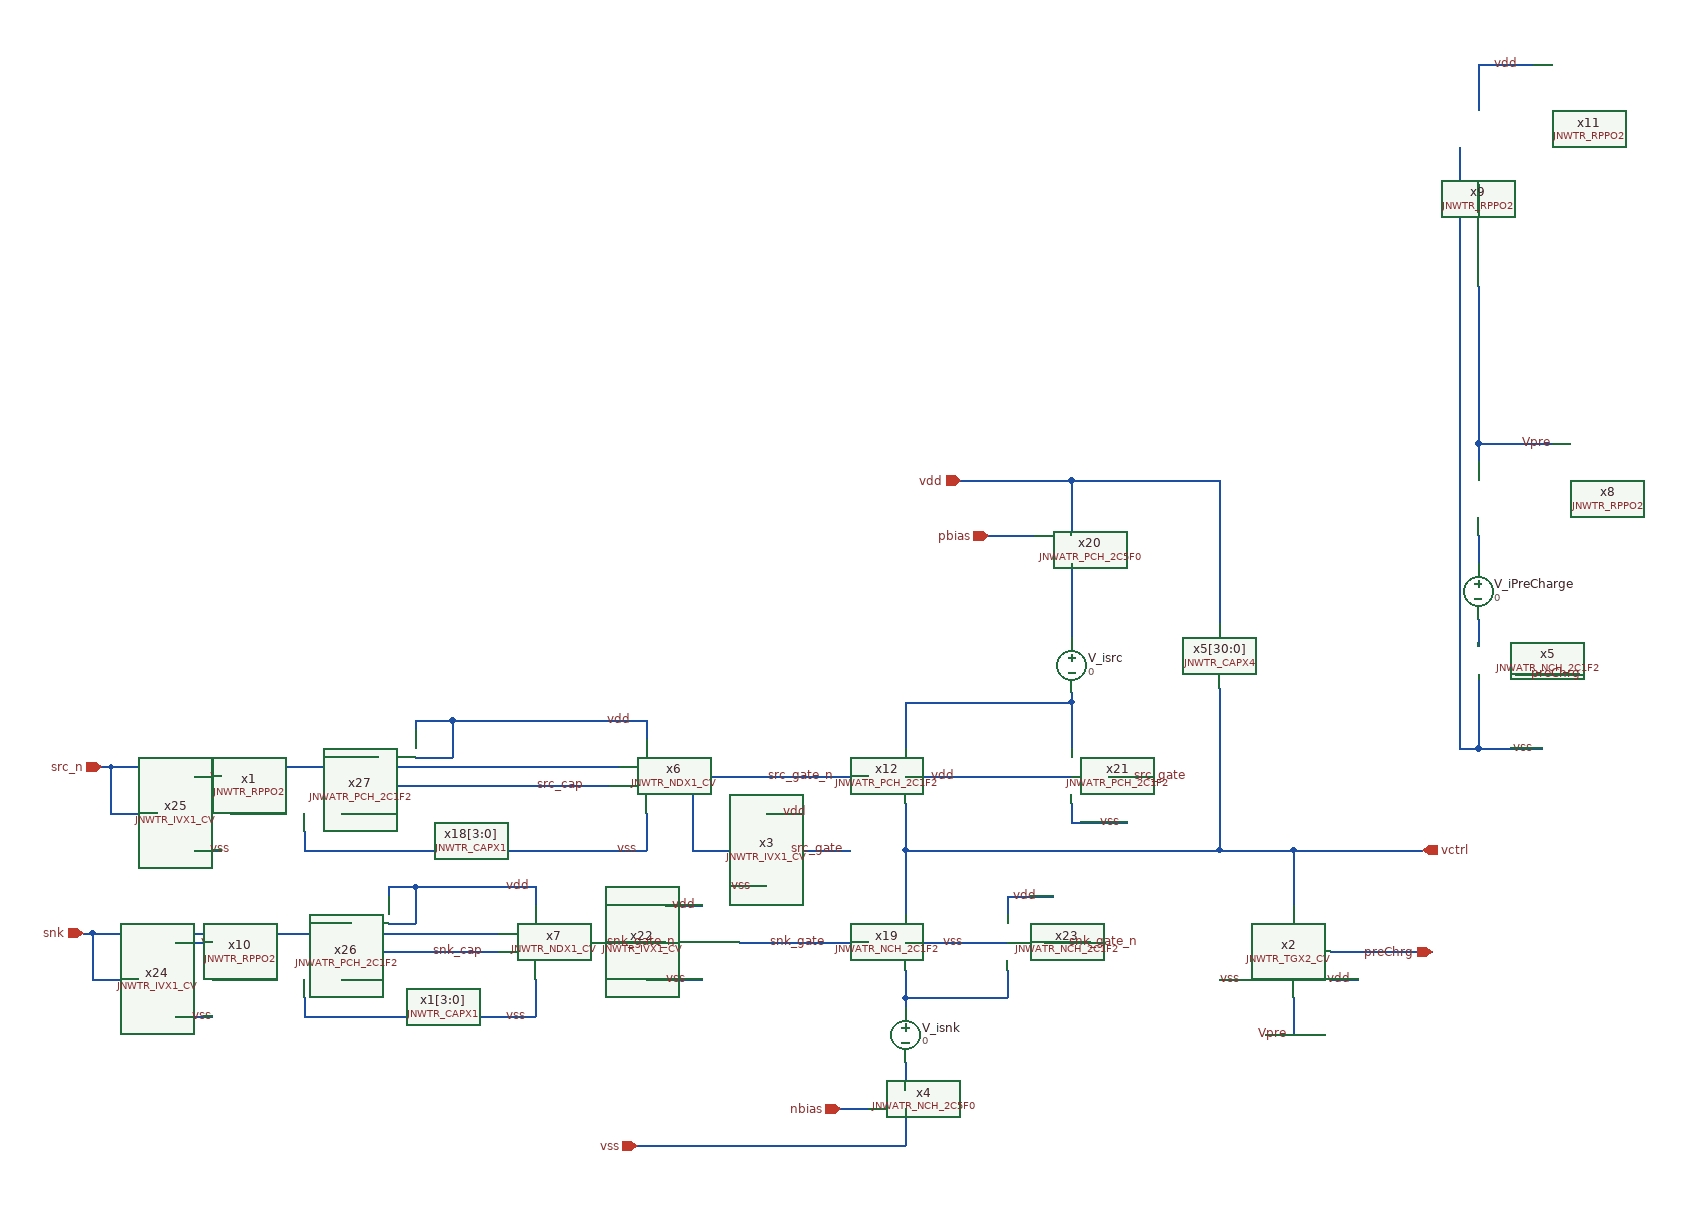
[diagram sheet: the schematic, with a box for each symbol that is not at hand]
v {xschem version=3.4.5 file_version=1.2
}
G {}
K {}
V {}
S {}
E {}
N 320 -700 440 -700 {
lab=vdd}
N 440 -700 440 -640 {
lab=vdd}
N 260 -20 260 20 {
lab=vss}
N 350 -640 400 -640 {
lab=pbias}
N 190 -20 220 -20 {
lab=nbias}
N 600 -475 600 -300 {
lab=vctrl}
N 600 -700 600 -545 {
lab=vdd}
N 720 -190 830 -190 {
lab=preChrg}
N 720 -160 750 -160 {
lab=vdd}
N 600 -160 630 -160 {
lab=vss}
N 680 -300 680 -240 {
lab=vctrl}
N 680 -300 820 -300 {
lab=vctrl}
N 600 -300 680 -300 {
lab=vctrl}
N 880 -740 960 -740 {
lab=Vpre}
N 680 -140 680 -100 {
lab=Vpre}
N 650 -100 680 -100 {
lab=Vpre}
N 260 -380 440 -380 {
lab=vdd}
N 260 -460 260 -410 {
lab=#net1}
N 260 -460 440 -460 {
lab=#net1}
N 260 -350 260 -300 {
lab=vctrl}
N 260 -300 600 -300 {
lab=vctrl}
N 440 -460 440 -410 {
lab=#net1}
N 440 -350 440 -330 {
lab=vss}
N 440 -330 500 -330 {
lab=vss}
N 480 -380 505 -380 {
lab=src_gate}
N -30 20 260 20 {
lab=vss}
N 370 -170 370 -140 {
lab=#net2}
N 260 -140 370 -140 {
lab=#net2}
N 260 -170 260 -140 {
lab=#net2}
N 370 -250 370 -230 {
lab=vdd}
N 370 -250 420 -250 {
lab=vdd}
N 410 -200 460 -200 {
lab=snk_gate_n}
N 440 -470 440 -460 {
lab=#net1}
N 260 -140 260 -130 {
lab=#net2}
N 260 -70 260 -40 {
lab=#net3}
N 260 -300 260 -230 {
lab=vctrl}
N 260 -200 370 -200 {
lab=vss}
N 440 -610 440 -530 {
lab=#net4}
N 440 -700 600 -700 {
lab=vdd}
N -380 -210 -180 -210 {
lab=snk}
N -20 -440 -20 -420 {
lab=vdd}
N -600 -390 -600 -340 {
lab=src_n}
N -610 -390 -600 -390 {
lab=src_n}
N -140 -260 -140 -240 {
lab=vdd}
N -140 -160 -140 -120 {
lab=vss}
N -620 -210 -620 -160 {
lab=snk}
N -330 -190 -330 -160 {
lab=snk_cap}
N -330 -190 -180 -190 {
lab=snk_cap}
N -320 -370 -320 -340 {
lab=src_cap}
N -390 -320 -390 -300 {
lab=vss}
N -20 -340 -20 -300 {
lab=vss}
N -320 -370 -60 -370 {
lab=src_cap}
N -350 -340 -320 -340 {
lab=src_cap}
N -390 -140 -390 -120 {
lab=vss}
N -350 -160 -330 -160 {
lab=snk_cap}
N 30 -380 220 -380 {
lab=src_gate_n}
N 95 -260 110 -260 {
lab=vss}
N 110 -340 125 -340 {
lab=vdd}
N 30 -380 30 -300 {
lab=src_gate_n}
N 30 -300 70 -300 {
lab=src_gate_n}
N 150 -300 200 -300 {
lab=src_gate}
N 80 -200 220 -200 {
lab=snk_gate}
N 0 -240 40 -240 {
lab=vdd}
N -510 -380 -480 -380 {
lab=vdd}
N -600 -340 -550 -340 {
lab=src_n}
N -470 -340 -430 -340 {
lab=#net5}
N -490 -160 -430 -160 {
lab=#net6}
N -620 -160 -570 -160 {
lab=snk}
N -530 -120 -490 -120 {
lab=vss}
N -530 -200 -490 -200 {
lab=vdd}
N -510 -300 -480 -300 {
lab=vss}
N -390 -300 -20 -300 {
lab=vss}
N -390 -120 -140 -120 {
lab=vss}
N -330 -390 -50 -390 {
lab=src_n}
N -20 -160 40 -160 {
lab=vss}
N -630 -210 -620 -210 {
lab=snk}
N -90 -200 0 -200 {
lab=snk_gate_n}
N -300 -260 -300 -250 {
lab=vdd}
N -270 -260 -140 -260 {
lab=vdd}
N -380 -220 -340 -220 {
lab=snk}
N -380 -220 -380 -210 {
lab=snk}
N -620 -210 -380 -210 {
lab=snk}
N -300 -220 -270 -220 {
lab=vdd}
N -270 -260 -270 -220 {
lab=vdd}
N -300 -260 -270 -260 {
lab=vdd}
N -330 -400 -310 -400 {
lab=src_n}
N -330 -400 -330 -390 {
lab=src_n}
N -600 -390 -330 -390 {
lab=src_n}
N -270 -440 -270 -430 {
lab=vdd}
N -230 -440 -20 -440 {
lab=vdd}
N -270 -400 -230 -400 {
lab=vdd}
N -230 -440 -230 -400 {
lab=vdd}
N -270 -440 -230 -440 {
lab=vdd}
N 880 -490 880 -410 {
lab=vss}
N 920 -490 990 -490 {
lab=preChrg}
N 880 -550 880 -520 {
lab=#net7}
N 880 -640 880 -610 {
lab=#net8}
N 880 -410 950 -410 {
lab=vss}
N 860 -410 880 -410 {
lab=vss}
N 880 -740 880 -720 {
lab=Vpre}
N 880 -1020 880 -990 {
lab=#net9}
N 880 -1150 880 -1100 {
lab=vdd}
N 880 -1150 940 -1150 {
lab=vdd}
N 880 -910 880 -740 {
lab=Vpre}
N 860 -1060 860 -410 {
lab=vss}
C {devices/ipin.sym} 320 -700 0 0 {name=p1 lab=vdd}
C {devices/opin.sym} 820 -300 0 0 {name=p2 lab=vctrl}
C {devices/ipin.sym} -30 20 0 0 {name=p3 lab=vss
}
C {devices/ipin.sym} 190 -20 0 0 {name=p6 lab=nbias
}
C {devices/ipin.sym} 350 -640 0 0 {name=p7 lab=pbias
}
C {JNW_TR_SKY130A/JNWTR_CAPX4.sym} 600 -485 0 0 {name=x5[30:0]}
C {devices/ipin.sym} 830 -190 2 0 {name=p10 lab=preChrg
}
C {devices/lab_wire.sym} 745 -160 0 0 {name=p8 sig_type=std_logic lab=vdd}
C {devices/lab_wire.sym} 895 -1150 0 1 {name=p19 sig_type=std_logic lab=vdd}
C {JNW_ATR_SKY130A/JNWATR_NCH_2C5F0.sym} 220 -20 0 0 {name=x4 }
C {devices/lab_wire.sym} 285 -380 0 1 {name=p22 sig_type=std_logic lab=vdd}
C {JNW_TR_SKY130A/JNWTR_TGX2_CV.sym} 680 -250 1 0 {name=x2 }
C {devices/lab_wire.sym} 915 -410 0 1 {name=p17 sig_type=std_logic lab=vss}
C {devices/lab_wire.sym} 625 -160 0 0 {name=p25 sig_type=std_logic lab=vss}
C {devices/lab_wire.sym} 925 -740 0 1 {name=p13 sig_type=std_logic lab=Vpre}
C {devices/lab_wire.sym} 675 -100 0 0 {name=p20 sig_type=std_logic lab=Vpre}
C {JNW_ATR_SKY130A/JNWATR_PCH_2C1F2.sym} 220 -380 0 0 {name=x12 }
C {JNW_ATR_SKY130A/JNWATR_NCH_2C1F2.sym} 220 -200 0 0 {name=x19 }
C {JNW_ATR_SKY130A/JNWATR_PCH_2C1F2.sym} 480 -380 0 1 {name=x21 }
C {devices/lab_wire.sym} 495 -330 0 0 {name=p26 sig_type=std_logic lab=vss}
C {devices/lab_wire.sym} 505 -380 0 1 {name=p28 sig_type=std_logic lab=src_gate}
C {JNW_ATR_SKY130A/JNWATR_NCH_2C1F2.sym} 410 -200 0 1 {name=x23 }
C {devices/lab_wire.sym} 325 -200 0 0 {name=p31 sig_type=std_logic lab=vss}
C {devices/lab_wire.sym} 405 -250 0 0 {name=p32 sig_type=std_logic lab=vdd}
C {devices/lab_wire.sym} 435 -200 0 1 {name=p33 sig_type=std_logic lab=snk_gate_n}
C {devices/vsource.sym} 440 -500 0 0 {name=V_isrc value=0 savecurrent=true}
C {devices/vsource.sym} 260 -100 0 0 {name=V_isnk value=0 savecurrent=true}
C {JNW_ATR_SKY130A/JNWATR_PCH_2C5F0.sym} 400 -640 0 0 {name=x20 }
C {devices/ipin.sym} -630 -210 0 0 {name=p9 lab=snk
}
C {devices/ipin.sym} -610 -390 0 0 {name=p11 lab=src_n}
C {devices/lab_wire.sym} -175 -260 0 1 {name=p14 sig_type=std_logic lab=vdd}
C {devices/lab_wire.sym} -175 -120 0 1 {name=p15 sig_type=std_logic lab=vss}
C {devices/lab_wire.sym} 185 -380 0 0 {name=p4 sig_type=std_logic lab=src_gate_n}
C {devices/lab_wire.sym} 175 -200 0 0 {name=p5 sig_type=std_logic lab=snk_gate}
C {devices/lab_wire.sym} -55 -300 0 1 {name=p12 sig_type=std_logic lab=vss}
C {devices/lab_wire.sym} -65 -440 0 1 {name=p16 sig_type=std_logic lab=vdd}
C {devices/lab_wire.sym} -85 -370 0 0 {name=p18 sig_type=std_logic lab=src_cap}
C {JNW_TR_SKY130A/JNWTR_CAPX1.sym} -210 -310 0 0 {name=x18[3:0]}
C {JNW_TR_SKY130A/JNWTR_CAPX1.sym} -240 -130 0 0 {name=x1[3:0]}
C {devices/lab_wire.sym} -195 -190 0 0 {name=p24 sig_type=std_logic lab=snk_cap}
C {JNW_TR_SKY130A/JNWTR_IVX1_CV.sym} 70 -300 0 0 {name=x3 }
C {devices/lab_wire.sym} 125 -340 0 1 {name=p21 sig_type=std_logic lab=vdd}
C {devices/lab_wire.sym} 95 -260 0 0 {name=p23 sig_type=std_logic lab=vss}
C {devices/lab_wire.sym} 195 -300 0 0 {name=p27 sig_type=std_logic lab=src_gate}
C {JNW_TR_SKY130A/JNWTR_IVX1_CV.sym} 0 -200 0 0 {name=x22 }
C {devices/lab_wire.sym} -65 -200 0 1 {name=p30 sig_type=std_logic lab=snk_gate_n}
C {JNW_TR_SKY130A/JNWTR_NDX1_CV.sym} -60 -370 0 0 {name=x6 }
C {JNW_TR_SKY130A/JNWTR_NDX1_CV.sym} -180 -190 0 0 {name=x7 }
C {devices/lab_wire.sym} 25 -160 0 0 {name=p34 sig_type=std_logic lab=vss}
C {devices/lab_wire.sym} 5 -240 0 1 {name=p35 sig_type=std_logic lab=vdd}
C {JNW_TR_SKY130A/JNWTR_IVX1_CV.sym} -570 -160 0 0 {name=x24 }
C {JNW_TR_SKY130A/JNWTR_IVX1_CV.sym} -550 -340 0 0 {name=x25 }
C {devices/lab_wire.sym} -515 -120 0 1 {name=p29 sig_type=std_logic lab=vss}
C {devices/lab_wire.sym} -495 -300 0 1 {name=p36 sig_type=std_logic lab=vss}
C {devices/lab_wire.sym} -505 -200 0 1 {name=p37 sig_type=std_logic lab=vdd}
C {devices/lab_wire.sym} -495 -380 0 1 {name=p38 sig_type=std_logic lab=vdd}
C {JNW_ATR_SKY130A/JNWATR_PCH_2C1F2.sym} -340 -220 0 0 {name=x26 }
C {JNW_ATR_SKY130A/JNWATR_PCH_2C1F2.sym} -310 -400 0 0 {name=x27 }
C {JNW_TR_SKY130A/JNWTR_RPPO2.sym} -430 -340 0 0 {name=x1 }
C {JNW_TR_SKY130A/JNWTR_RPPO2.sym} -430 -160 0 0 {name=x10 }
C {devices/vsource.sym} 880 -580 0 0 {name=V_iPreCharge value=0 savecurrent=true}
C {JNW_ATR_SKY130A/JNWATR_NCH_2C1F2.sym} 920 -490 0 1 {name=x5 }
C {devices/lab_wire.sym} 935 -490 0 1 {name=p39 sig_type=std_logic lab=preChrg}
C {JNW_TR_SKY130A/JNWTR_RPPO2.sym} 880 -720 1 0 {name=x8 }
C {JNW_TR_SKY130A/JNWTR_RPPO2.sym} 880 -990 1 0 {name=x9 }
C {JNW_TR_SKY130A/JNWTR_RPPO2.sym} 880 -1100 1 0 {name=x11 }
